VERSION 5.7 ;
  NOWIREEXTENSIONATPIN ON ;
  DIVIDERCHAR "/" ;
  BUSBITCHARS "[]" ;
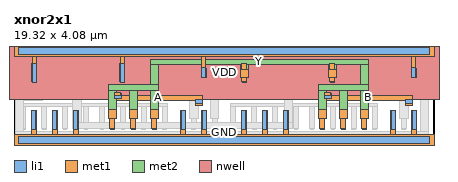
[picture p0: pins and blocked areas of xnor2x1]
MACRO xnor2x1
  CLASS BLOCK ;
  FOREIGN xnor2x1 ;
  ORIGIN 0.000 0.000 ;
  SIZE 19.320 BY 4.080 ;
  PIN A
    ANTENNAGATEAREA 1.323000 ;
    PORT
      LAYER li1 ;
        RECT 4.605 1.930 4.935 2.120 ;
        RECT 8.345 1.660 8.675 1.850 ;
      LAYER met1 ;
        RECT 4.620 2.070 4.920 2.190 ;
        RECT 4.620 1.830 8.660 2.070 ;
        RECT 8.360 1.600 8.660 1.830 ;
    END
  END A
  PIN B
    ANTENNAGATEAREA 1.323000 ;
    PORT
      LAYER li1 ;
        RECT 14.265 1.930 14.595 2.120 ;
        RECT 18.005 1.660 18.335 1.850 ;
      LAYER met1 ;
        RECT 14.280 2.070 14.580 2.190 ;
        RECT 14.280 1.830 18.320 2.070 ;
        RECT 18.020 1.600 18.320 1.830 ;
    END
  END B
  PIN Y
    ANTENNADIFFAREA 2.150400 ;
    PORT
      LAYER li1 ;
        RECT 10.505 2.660 10.675 3.540 ;
        RECT 14.565 2.660 14.735 3.540 ;
        RECT 4.445 0.490 4.615 1.370 ;
        RECT 5.405 0.490 5.575 1.370 ;
        RECT 6.365 0.490 6.535 1.370 ;
        RECT 14.105 0.490 14.275 1.370 ;
        RECT 15.065 0.490 15.235 1.370 ;
        RECT 16.025 0.490 16.195 1.370 ;
      LAYER met1 ;
        RECT 10.475 3.260 10.705 3.520 ;
        RECT 14.535 3.260 14.765 3.520 ;
        RECT 10.410 2.880 10.770 3.260 ;
        RECT 14.470 2.880 14.830 3.260 ;
        RECT 10.475 2.680 10.705 2.880 ;
        RECT 14.535 2.680 14.765 2.880 ;
        RECT 4.340 1.010 4.720 1.390 ;
        RECT 5.300 1.010 5.680 1.390 ;
        RECT 6.260 1.010 6.640 1.390 ;
        RECT 14.000 1.010 14.380 1.390 ;
        RECT 14.960 1.010 15.340 1.390 ;
        RECT 15.920 1.010 16.300 1.390 ;
        RECT 4.415 0.510 4.645 1.010 ;
        RECT 5.375 0.510 5.605 1.010 ;
        RECT 6.335 0.510 6.565 1.010 ;
        RECT 14.075 0.510 14.305 1.010 ;
        RECT 15.035 0.510 15.265 1.010 ;
        RECT 15.995 0.510 16.225 1.010 ;
      LAYER met2 ;
        RECT 6.260 3.460 16.300 3.720 ;
        RECT 6.260 2.560 6.640 3.460 ;
        RECT 10.400 2.880 10.780 3.460 ;
        RECT 14.460 2.880 14.840 3.460 ;
        RECT 15.920 2.560 16.300 3.460 ;
        RECT 4.340 2.300 6.640 2.560 ;
        RECT 4.340 1.010 4.720 2.300 ;
        RECT 5.300 1.010 5.680 2.300 ;
        RECT 6.260 1.010 6.640 2.300 ;
        RECT 14.000 2.300 16.300 2.560 ;
        RECT 14.000 1.010 14.380 2.300 ;
        RECT 14.960 1.010 15.340 2.300 ;
        RECT 15.920 1.010 16.300 2.300 ;
    END
  END Y
  PIN VDD
    ANTENNADIFFAREA 6.229200 ;
    PORT
      LAYER nwell ;
        RECT -0.230 1.870 19.550 4.410 ;
      LAYER li1 ;
        RECT 0.210 3.915 19.110 4.245 ;
        RECT 0.845 2.660 1.015 3.540 ;
        RECT 4.905 2.660 5.075 3.540 ;
        RECT 8.645 2.870 8.815 3.330 ;
        RECT 18.305 2.870 18.475 3.330 ;
      LAYER met1 ;
        RECT 0.000 3.840 19.320 4.320 ;
        RECT 0.845 3.520 1.015 3.840 ;
        RECT 4.905 3.520 5.075 3.840 ;
        RECT 0.815 2.680 1.045 3.520 ;
        RECT 4.875 2.680 5.105 3.520 ;
        RECT 8.645 3.310 8.815 3.840 ;
        RECT 18.305 3.310 18.475 3.840 ;
        RECT 8.615 2.890 8.845 3.310 ;
        RECT 18.275 2.890 18.505 3.310 ;
    END
  END VDD
  PIN GND
    ANTENNADIFFAREA 8.236800 ;
    PORT
      LAYER li1 ;
        RECT 0.825 0.490 0.995 1.370 ;
        RECT 1.785 0.490 1.955 1.370 ;
        RECT 2.745 0.490 2.915 1.370 ;
        RECT 7.705 0.490 7.875 1.370 ;
        RECT 8.665 0.490 8.835 1.370 ;
        RECT 10.485 0.490 10.655 1.370 ;
        RECT 11.445 0.490 11.615 1.370 ;
        RECT 12.405 0.490 12.575 1.370 ;
        RECT 17.365 0.490 17.535 1.370 ;
        RECT 18.325 0.490 18.495 1.370 ;
        RECT 0.210 -0.165 19.110 0.165 ;
      LAYER met1 ;
        RECT 0.795 0.240 1.025 1.350 ;
        RECT 1.755 0.240 1.985 1.350 ;
        RECT 2.715 0.240 2.945 1.350 ;
        RECT 7.675 0.240 7.905 1.350 ;
        RECT 8.635 0.240 8.865 1.350 ;
        RECT 10.455 0.240 10.685 1.350 ;
        RECT 11.415 0.240 11.645 1.350 ;
        RECT 12.375 0.240 12.605 1.350 ;
        RECT 17.335 0.240 17.565 1.350 ;
        RECT 18.295 0.240 18.525 1.350 ;
        RECT 0.000 -0.240 19.320 0.240 ;
    END
  END GND
  OBS
      LAYER li1 ;
        RECT 1.285 2.660 1.455 3.540 ;
        RECT 4.465 2.660 4.635 3.540 ;
        RECT 8.205 2.870 8.375 3.330 ;
        RECT 10.945 2.660 11.115 3.540 ;
        RECT 14.125 2.660 14.295 3.540 ;
        RECT 17.865 2.870 18.035 3.330 ;
        RECT 0.985 1.930 1.315 2.120 ;
        RECT 10.645 1.930 10.975 2.120 ;
        RECT 0.345 0.490 0.515 1.370 ;
        RECT 1.305 0.490 1.475 1.370 ;
        RECT 2.265 0.490 2.435 1.370 ;
        RECT 3.225 0.490 3.395 1.370 ;
        RECT 3.965 0.490 4.135 1.370 ;
        RECT 4.925 0.490 5.095 1.370 ;
        RECT 5.885 0.490 6.055 1.370 ;
        RECT 6.845 0.490 7.015 1.370 ;
        RECT 8.185 0.490 8.355 1.370 ;
        RECT 9.145 0.490 9.315 1.370 ;
        RECT 10.005 0.490 10.175 1.370 ;
        RECT 10.965 0.490 11.135 1.370 ;
        RECT 11.925 0.490 12.095 1.370 ;
        RECT 12.885 0.490 13.055 1.370 ;
        RECT 13.625 0.490 13.795 1.370 ;
        RECT 14.585 0.490 14.755 1.370 ;
        RECT 15.545 0.490 15.715 1.370 ;
        RECT 16.505 0.490 16.675 1.370 ;
        RECT 17.845 0.490 18.015 1.370 ;
        RECT 18.805 0.490 18.975 1.370 ;
      LAYER met1 ;
        RECT 1.255 3.200 1.485 3.520 ;
        RECT 2.710 3.200 3.090 3.290 ;
        RECT 4.435 3.200 4.665 3.520 ;
        RECT 8.175 3.260 8.405 3.310 ;
        RECT 1.255 3.000 4.665 3.200 ;
        RECT 1.255 2.680 1.485 3.000 ;
        RECT 2.710 2.910 3.090 3.000 ;
        RECT 4.435 2.680 4.665 3.000 ;
        RECT 8.100 2.880 8.460 3.260 ;
        RECT 10.915 3.200 11.145 3.520 ;
        RECT 12.450 3.200 12.830 3.290 ;
        RECT 14.095 3.200 14.325 3.520 ;
        RECT 17.835 3.260 18.065 3.310 ;
        RECT 10.915 3.000 14.325 3.200 ;
        RECT 10.915 2.680 11.145 3.000 ;
        RECT 12.450 2.910 12.830 3.000 ;
        RECT 14.095 2.680 14.325 3.000 ;
        RECT 17.760 2.880 18.120 3.260 ;
        RECT 8.080 2.520 9.420 2.590 ;
        RECT 8.080 2.210 10.960 2.520 ;
        RECT 17.740 2.210 19.080 2.590 ;
        RECT 0.070 2.070 0.450 2.210 ;
        RECT 1.000 2.070 1.300 2.190 ;
        RECT 9.420 2.140 10.960 2.210 ;
        RECT 0.070 1.830 1.300 2.070 ;
        RECT 10.660 1.870 10.960 2.140 ;
        RECT 0.315 1.540 7.045 1.690 ;
        RECT 0.315 0.510 0.545 1.540 ;
        RECT 1.275 0.510 1.505 1.540 ;
        RECT 2.235 0.510 2.465 1.540 ;
        RECT 3.195 0.510 3.425 1.540 ;
        RECT 3.935 0.510 4.165 1.540 ;
        RECT 4.895 0.510 5.125 1.540 ;
        RECT 5.855 0.510 6.085 1.540 ;
        RECT 6.815 0.510 7.045 1.540 ;
        RECT 9.975 1.540 16.705 1.690 ;
        RECT 8.080 1.010 8.460 1.390 ;
        RECT 9.040 1.010 9.420 1.390 ;
        RECT 8.155 0.510 8.385 1.010 ;
        RECT 9.115 0.510 9.345 1.010 ;
        RECT 9.975 0.510 10.205 1.540 ;
        RECT 10.935 0.510 11.165 1.540 ;
        RECT 11.895 0.510 12.125 1.540 ;
        RECT 12.855 0.510 13.085 1.540 ;
        RECT 13.595 0.510 13.825 1.540 ;
        RECT 14.555 0.510 14.785 1.540 ;
        RECT 15.515 0.510 15.745 1.540 ;
        RECT 16.475 0.510 16.705 1.540 ;
        RECT 17.740 1.010 18.120 1.390 ;
        RECT 18.700 1.010 19.080 1.390 ;
        RECT 17.815 0.510 18.045 1.010 ;
        RECT 18.775 0.510 19.005 1.010 ;
      LAYER met2 ;
        RECT 0.070 0.400 0.450 2.150 ;
        RECT 2.710 0.800 3.090 3.230 ;
        RECT 8.080 1.010 8.470 3.260 ;
        RECT 9.040 1.010 9.420 2.590 ;
        RECT 12.450 0.800 12.830 3.230 ;
        RECT 17.740 1.010 18.130 3.260 ;
        RECT 2.710 0.540 12.830 0.800 ;
        RECT 18.700 0.400 19.080 2.590 ;
        RECT 0.070 0.140 19.080 0.400 ;
  END
END xnor2x1
END LIBRARY

